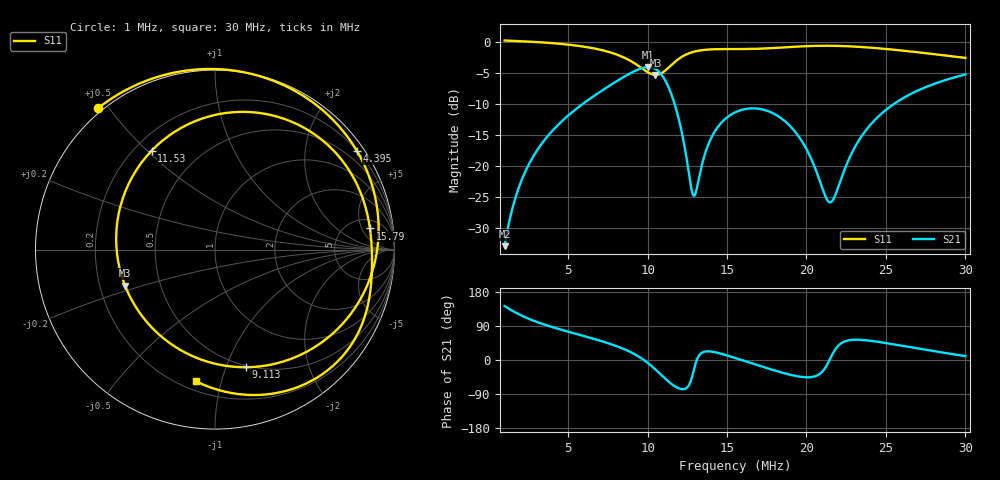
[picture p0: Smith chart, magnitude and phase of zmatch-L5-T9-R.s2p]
# HZ S RI R 50
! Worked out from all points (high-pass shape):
!   505 points, 1 MHz to 30 MHz, reference 50 ohm
!   highest |S21| = -4.10 dB at 10.03 MHz (marker M1); lowest = -32.9 dB at 1 MHz (marker M2)
!   |S21| within 3 dB of the highest: 7.592 MHz to 11.28 MHz (3.686 MHz wide, 39.1 % of centre); 27.71 MHz to end of sweep
!   lowest |S11| = -5.4 dB at 10.49 MHz (marker M3), VSWR 3.35, Z = 15.4 - j8.72 ohm
!   |S11| at or under -10 dB: nowhere
!   S12 and S22 are empty: the file has one direction only
!   S11 on the Smith chart (normalised r, x): 1 MHz: -0.01, +0.47; 4.395 MHz: 0.21, +3.19; 9.113 MHz: 0.48, -1.17; 11.53 MHz: 0.27, +0.52; 15.79 MHz: 7, +7; 30 MHz: 0.26, -0.83
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1000000  -0.6514 0.7875  -0.0179 0.0138  0 0  0 0
2380960  0.1191 0.9953  -0.0342 0.0881  0 0  0 0
3359140  0.5286 0.8321  -0.0148 0.1516  0 0  0 0
4394860  0.7916 0.5482  0.0301 0.2136  0 0  0 0
5833360  0.9117 0.1028  0.1304 0.2808  0 0  0 0
7559560  0.7226 -0.4001  0.3171 0.3032  0 0  0 0
9113140  0.1713 -0.6556  0.5491 0.1672  0 0  0 0
1.003378e7  -0.3166 -0.4688  0.6166 -0.0917  0 0  0 0
1.04941e7  -0.5016 -0.2002  0.5456 -0.2539  0 0  0 0
1.066672e7  -0.5381 -0.0733  0.4938 -0.3043  0 0  0 0
1.152982e7  -0.353 0.5511  0.1614 -0.3295  0 0  0 0
1.216276e7  0.0255 0.7555  0.0415 -0.1789  0 0  0 0
1.291078e7  0.4191 0.7157  0.0514 -0.0257  0 0  0 0
1.406158e7  0.7363 0.4582  0.1612 0.0649  0 0  0 0
1.550008e7  0.8551 0.1653  0.2681 0.0268  0 0  0 0
1.578778e7  0.8632 0.1176  0.2788 0.00909  0 0  0 0
1.831954e7  0.8667 -0.2204  0.2097 -0.1293  0 0  0 0
2.033344e7  0.7977 -0.4638  0.0788 -0.0788  0 0  0 0
2.154178e7  0.7113 -0.5931  0.0507 0.00693  0 0  0 0
2.326798e7  0.5449 -0.727  0.0943 0.1273  0 0  0 0
2.51668e7  0.3413 -0.7993  0.2126 0.2021  0 0  0 0
3.000016e7  -0.1085 -0.7321  0.5355 0.0957  0 0  0 0
